VERSION 5.7 ;
  NOWIREEXTENSIONATPIN ON ;
  DIVIDERCHAR "/" ;
  BUSBITCHARS "[]" ;
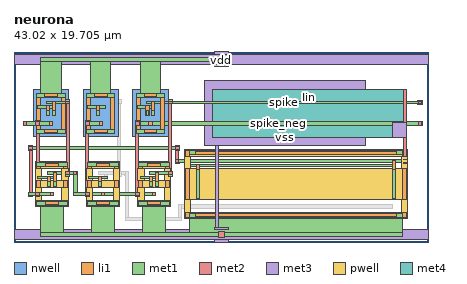
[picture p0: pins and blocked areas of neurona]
MACRO neurona
  CLASS BLOCK ;
  FOREIGN neurona ;
  ORIGIN 0.000 0.000 ;
  SIZE 43.020 BY 19.705 ;
  PIN vdd
    USE POWER ;
    PORT
      LAYER nwell ;
        RECT 2.000 10.930 5.660 15.780 ;
        RECT 7.160 10.930 10.820 15.780 ;
        RECT 12.320 10.930 15.980 15.780 ;
      LAYER li1 ;
        RECT 2.360 11.290 2.770 15.420 ;
        RECT 3.165 15.050 4.495 15.380 ;
        RECT 3.360 13.105 3.690 14.120 ;
        RECT 3.165 11.330 4.495 11.660 ;
        RECT 4.890 11.290 5.300 15.420 ;
        RECT 7.520 11.290 7.930 15.420 ;
        RECT 8.325 15.050 9.655 15.380 ;
        RECT 8.520 13.105 8.850 14.120 ;
        RECT 8.325 11.330 9.655 11.660 ;
        RECT 10.050 11.290 10.460 15.420 ;
        RECT 12.680 11.290 13.090 15.420 ;
        RECT 13.485 15.050 14.815 15.380 ;
        RECT 13.680 13.105 14.010 14.120 ;
        RECT 13.485 11.330 14.815 11.660 ;
        RECT 15.210 11.290 15.620 15.420 ;
      LAYER met1 ;
        RECT 2.770 18.740 21.725 19.170 ;
        RECT 2.770 15.420 4.890 18.740 ;
        RECT 7.930 15.420 10.050 18.740 ;
        RECT 13.090 15.420 15.210 18.740 ;
        RECT 2.360 15.010 5.300 15.420 ;
        RECT 7.520 15.010 10.460 15.420 ;
        RECT 12.680 15.010 15.620 15.420 ;
        RECT 2.480 13.890 4.280 14.180 ;
        RECT 7.640 13.890 9.440 14.180 ;
        RECT 12.800 13.890 14.600 14.180 ;
        RECT 3.380 13.105 3.670 13.605 ;
        RECT 8.540 13.105 8.830 13.605 ;
        RECT 13.700 13.105 13.990 13.605 ;
        RECT 2.360 11.290 5.300 11.700 ;
        RECT 7.520 11.290 10.460 11.700 ;
        RECT 12.680 11.290 15.620 11.700 ;
      LAYER met2 ;
        RECT 21.220 18.665 21.800 19.245 ;
      LAYER met3 ;
        RECT 20.760 19.455 22.260 19.705 ;
        RECT 0.000 18.455 43.020 19.455 ;
        RECT 20.760 18.205 22.260 18.455 ;
    END
  END vdd
  PIN vss
    USE GROUND ;
    PORT
      LAYER pwell ;
        RECT 17.660 8.910 40.840 9.580 ;
        RECT 2.180 7.660 5.640 8.330 ;
        RECT 2.180 6.385 2.850 7.660 ;
        RECT 4.970 6.385 5.640 7.660 ;
        RECT 2.180 5.625 5.640 6.385 ;
        RECT 2.180 4.350 2.850 5.625 ;
        RECT 4.970 4.350 5.640 5.625 ;
        RECT 2.180 3.680 5.640 4.350 ;
        RECT 7.500 7.660 10.960 8.330 ;
        RECT 7.500 6.385 8.170 7.660 ;
        RECT 10.290 6.385 10.960 7.660 ;
        RECT 7.500 5.625 10.960 6.385 ;
        RECT 7.500 4.350 8.170 5.625 ;
        RECT 10.290 4.350 10.960 5.625 ;
        RECT 7.500 3.680 10.960 4.350 ;
        RECT 12.820 7.660 16.280 8.330 ;
        RECT 12.820 6.385 13.490 7.660 ;
        RECT 15.610 6.385 16.280 7.660 ;
        RECT 12.820 5.625 16.280 6.385 ;
        RECT 12.820 4.350 13.490 5.625 ;
        RECT 15.610 4.350 16.280 5.625 ;
        RECT 12.820 3.680 16.280 4.350 ;
        RECT 17.660 7.635 18.330 8.910 ;
        RECT 40.170 7.635 40.840 8.910 ;
        RECT 17.660 4.375 40.840 7.635 ;
        RECT 17.660 3.100 18.330 4.375 ;
        RECT 40.170 3.100 40.840 4.375 ;
        RECT 17.660 2.430 40.840 3.100 ;
      LAYER li1 ;
        RECT 2.310 3.810 2.720 8.200 ;
        RECT 3.245 7.830 4.575 8.160 ;
        RECT 3.440 5.755 3.770 6.770 ;
        RECT 3.245 3.850 4.575 4.180 ;
        RECT 5.100 3.810 5.510 8.200 ;
        RECT 7.630 3.810 8.040 8.200 ;
        RECT 8.565 7.830 9.895 8.160 ;
        RECT 8.760 5.755 9.090 6.770 ;
        RECT 8.565 3.850 9.895 4.180 ;
        RECT 10.420 3.810 10.830 8.200 ;
        RECT 12.950 3.810 13.360 8.200 ;
        RECT 13.885 7.830 15.215 8.160 ;
        RECT 14.080 5.755 14.410 6.770 ;
        RECT 13.885 3.850 15.215 4.180 ;
        RECT 15.740 3.810 16.150 8.200 ;
        RECT 17.790 2.560 18.200 9.450 ;
        RECT 18.835 9.080 39.665 9.410 ;
        RECT 18.920 4.505 19.250 8.020 ;
        RECT 18.835 2.600 39.665 2.930 ;
        RECT 40.300 2.560 40.710 9.450 ;
      LAYER met1 ;
        RECT 17.790 9.040 40.710 9.450 ;
        RECT 2.310 7.790 5.510 8.200 ;
        RECT 7.630 7.790 10.830 8.200 ;
        RECT 12.950 7.790 16.150 8.200 ;
        RECT 17.910 7.790 39.560 8.080 ;
        RECT 2.430 6.540 4.360 6.830 ;
        RECT 7.750 6.540 9.680 6.830 ;
        RECT 13.070 6.540 15.000 6.830 ;
        RECT 3.460 5.755 3.750 6.255 ;
        RECT 8.780 5.755 9.070 6.255 ;
        RECT 14.100 5.755 14.390 6.255 ;
        RECT 18.940 4.505 19.230 7.505 ;
        RECT 2.310 3.810 5.510 4.220 ;
        RECT 7.630 3.810 10.830 4.220 ;
        RECT 12.950 3.810 16.150 4.220 ;
        RECT 2.720 0.965 5.100 3.810 ;
        RECT 8.040 0.965 10.420 3.810 ;
        RECT 13.360 0.965 15.740 3.810 ;
        RECT 17.790 2.560 40.710 2.970 ;
        RECT 18.200 0.965 40.300 2.560 ;
        RECT 2.720 0.535 40.300 0.965 ;
      LAYER met2 ;
        RECT 21.220 0.460 21.800 1.040 ;
      LAYER met3 ;
        RECT 19.710 10.005 36.410 16.705 ;
        RECT 20.850 1.500 21.230 10.005 ;
        RECT 20.760 1.250 22.260 1.500 ;
        RECT 0.000 0.250 43.020 1.250 ;
        RECT 20.760 0.000 22.260 0.250 ;
    END
  END vss
  PIN Iin
    ANTENNAGATEAREA 0.280000 ;
    ANTENNADIFFAREA 1.170000 ;
    PORT
      LAYER li1 ;
        RECT 3.665 12.125 3.995 12.455 ;
        RECT 3.745 4.775 4.075 5.105 ;
        RECT 39.250 4.505 39.580 8.450 ;
      LAYER met1 ;
        RECT 0.950 12.455 1.380 12.505 ;
        RECT 2.235 12.455 2.665 12.555 ;
        RECT 0.950 12.125 3.995 12.455 ;
        RECT 0.950 12.075 1.380 12.125 ;
        RECT 1.480 9.910 1.910 9.960 ;
        RECT 16.775 9.910 17.205 9.960 ;
        RECT 1.480 9.580 17.205 9.910 ;
        RECT 1.480 9.530 1.910 9.580 ;
        RECT 16.775 9.530 17.205 9.580 ;
        RECT 16.725 8.510 17.155 8.580 ;
        RECT 40.345 8.510 40.775 8.580 ;
        RECT 16.725 8.220 40.775 8.510 ;
        RECT 16.725 8.150 17.155 8.220 ;
        RECT 40.345 8.150 40.775 8.220 ;
        RECT 1.530 5.105 1.960 5.155 ;
        RECT 1.530 4.775 4.075 5.105 ;
        RECT 1.530 4.725 1.960 4.775 ;
        RECT 2.235 4.675 2.665 4.775 ;
        RECT 39.270 4.505 39.560 7.505 ;
      LAYER met2 ;
        RECT 1.000 12.125 1.330 12.455 ;
        RECT 2.235 12.125 2.665 12.555 ;
        RECT 40.395 12.355 40.725 15.855 ;
        RECT 1.480 9.530 1.910 9.960 ;
        RECT 1.580 4.775 1.910 9.530 ;
        RECT 2.285 5.105 2.615 12.125 ;
        RECT 39.225 10.855 40.725 12.355 ;
        RECT 16.775 9.530 17.205 9.960 ;
        RECT 16.775 8.200 17.105 9.530 ;
        RECT 40.395 8.200 40.725 10.855 ;
        RECT 2.235 4.675 2.665 5.105 ;
      LAYER met3 ;
        RECT 39.225 10.855 40.725 12.355 ;
      LAYER met4 ;
        RECT 20.560 10.855 40.725 15.855 ;
    END
  END Iin
  PIN spike_neg
    ANTENNAGATEAREA 0.560000 ;
    ANTENNADIFFAREA 0.390000 ;
    PORT
      LAYER li1 ;
        RECT 3.970 13.105 4.300 14.550 ;
        RECT 8.825 12.125 9.155 12.455 ;
        RECT 13.985 12.125 14.315 12.455 ;
        RECT 4.050 5.755 4.380 7.200 ;
        RECT 9.065 4.775 9.395 5.105 ;
        RECT 14.385 4.775 14.715 5.105 ;
      LAYER met1 ;
        RECT 5.360 14.610 5.790 14.750 ;
        RECT 3.380 14.320 5.790 14.610 ;
        RECT 3.990 13.105 4.280 13.605 ;
        RECT 7.395 12.455 7.825 12.555 ;
        RECT 12.555 12.455 12.985 12.555 ;
        RECT 41.885 12.455 42.315 12.505 ;
        RECT 7.395 12.125 9.155 12.455 ;
        RECT 12.555 12.125 42.315 12.455 ;
        RECT 41.885 12.075 42.315 12.125 ;
        RECT 6.145 7.260 6.575 7.330 ;
        RECT 3.460 6.970 6.575 7.260 ;
        RECT 5.360 6.830 5.790 6.970 ;
        RECT 4.070 5.755 4.360 6.255 ;
        RECT 6.145 5.105 6.575 6.970 ;
        RECT 6.145 4.775 14.715 5.105 ;
        RECT 7.395 4.675 7.825 4.775 ;
        RECT 12.555 4.675 12.985 4.775 ;
      LAYER met2 ;
        RECT 5.360 14.320 5.790 14.750 ;
        RECT 5.430 7.260 5.720 14.320 ;
        RECT 7.395 12.125 7.825 12.555 ;
        RECT 12.555 12.125 12.985 12.555 ;
        RECT 41.935 12.125 42.265 12.455 ;
        RECT 5.360 6.830 5.790 7.260 ;
        RECT 6.195 6.950 6.525 7.280 ;
        RECT 7.445 5.105 7.775 12.125 ;
        RECT 12.605 5.105 12.935 12.125 ;
        RECT 7.395 4.675 7.825 5.105 ;
        RECT 12.555 4.675 12.985 5.105 ;
    END
  END spike_neg
  PIN spike
    ANTENNADIFFAREA 0.390000 ;
    PORT
      LAYER li1 ;
        RECT 14.290 13.105 14.620 14.550 ;
        RECT 14.690 5.755 15.020 7.200 ;
      LAYER met1 ;
        RECT 16.000 14.610 16.430 14.750 ;
        RECT 41.885 14.610 42.315 14.680 ;
        RECT 13.700 14.320 42.315 14.610 ;
        RECT 41.885 14.250 42.315 14.320 ;
        RECT 14.310 13.105 14.600 13.605 ;
        RECT 14.100 6.970 16.430 7.260 ;
        RECT 16.000 6.830 16.430 6.970 ;
        RECT 14.710 5.755 15.000 6.255 ;
      LAYER met2 ;
        RECT 16.000 14.320 16.430 14.750 ;
        RECT 16.070 7.260 16.360 14.320 ;
        RECT 41.935 14.300 42.265 14.630 ;
        RECT 16.000 6.830 16.430 7.260 ;
    END
  END spike
  OBS
      LAYER li1 ;
        RECT 9.130 13.105 9.460 14.550 ;
        RECT 9.370 5.755 9.700 7.200 ;
        RECT 19.585 3.525 19.915 3.855 ;
        RECT 20.085 3.525 20.415 3.855 ;
        RECT 20.585 3.525 20.915 3.855 ;
        RECT 21.085 3.525 21.415 3.855 ;
        RECT 21.585 3.525 21.915 3.855 ;
        RECT 22.085 3.525 22.415 3.855 ;
        RECT 22.585 3.525 22.915 3.855 ;
        RECT 23.085 3.525 23.415 3.855 ;
        RECT 23.585 3.525 23.915 3.855 ;
        RECT 24.085 3.525 24.415 3.855 ;
        RECT 24.585 3.525 24.915 3.855 ;
        RECT 25.085 3.525 25.415 3.855 ;
        RECT 25.585 3.525 25.915 3.855 ;
        RECT 26.085 3.525 26.415 3.855 ;
        RECT 26.585 3.525 26.915 3.855 ;
        RECT 27.085 3.525 27.415 3.855 ;
        RECT 27.585 3.525 27.915 3.855 ;
        RECT 28.085 3.525 28.415 3.855 ;
        RECT 28.585 3.525 28.915 3.855 ;
        RECT 29.085 3.525 29.415 3.855 ;
        RECT 29.585 3.525 29.915 3.855 ;
        RECT 30.085 3.525 30.415 3.855 ;
        RECT 30.585 3.525 30.915 3.855 ;
        RECT 31.085 3.525 31.415 3.855 ;
        RECT 31.585 3.525 31.915 3.855 ;
        RECT 32.085 3.525 32.415 3.855 ;
        RECT 32.585 3.525 32.915 3.855 ;
        RECT 33.085 3.525 33.415 3.855 ;
        RECT 33.585 3.525 33.915 3.855 ;
        RECT 34.085 3.525 34.415 3.855 ;
        RECT 34.585 3.525 34.915 3.855 ;
        RECT 35.085 3.525 35.415 3.855 ;
        RECT 35.585 3.525 35.915 3.855 ;
        RECT 36.085 3.525 36.415 3.855 ;
        RECT 36.585 3.525 36.915 3.855 ;
        RECT 37.085 3.525 37.415 3.855 ;
        RECT 37.585 3.525 37.915 3.855 ;
        RECT 38.085 3.525 38.415 3.855 ;
        RECT 38.585 3.525 38.915 3.855 ;
      LAYER met1 ;
        RECT 10.680 14.610 11.110 14.750 ;
        RECT 8.540 14.320 11.110 14.610 ;
        RECT 9.150 13.105 9.440 13.605 ;
        RECT 11.465 7.260 11.895 7.330 ;
        RECT 8.780 6.970 11.895 7.260 ;
        RECT 10.680 6.830 11.110 6.970 ;
        RECT 11.465 6.900 11.895 6.970 ;
        RECT 9.390 5.755 9.680 6.255 ;
        RECT 17.035 3.855 17.465 3.905 ;
        RECT 17.035 3.525 39.250 3.855 ;
        RECT 17.035 3.475 17.465 3.525 ;
      LAYER met2 ;
        RECT 10.680 14.320 11.110 14.750 ;
        RECT 10.750 7.260 11.040 14.320 ;
        RECT 10.680 6.830 11.110 7.260 ;
        RECT 11.515 2.550 11.845 7.280 ;
        RECT 17.085 2.550 17.415 3.855 ;
        RECT 11.515 2.220 17.415 2.550 ;
  END
END neurona
END LIBRARY

